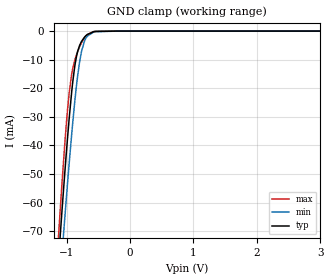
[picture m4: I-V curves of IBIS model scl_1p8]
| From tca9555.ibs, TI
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|   scl_1p8 Model
[Model]   scl_1p8
Model_type   Input
Vinl = 0.54
Vinh = 1.26
|   typ   min   max
|   (nom PVT)   (fast PVT)   (slow PVT)
C_comp   1.340e-12   1.280e-12   1.437e-12
[Model spec]
|subparameter
Vinl   0.54   0.495   0.585
Vinh   1.26   1.155   1.365
| Where nom  PVT is Nominal Process, 1.8V, 27C
|   Fast PVT is Strong Process,  1.95V, -40C
|   Slow PVT is Weak Process,   1.65V, 100C
[Voltage Range]   1.8   1.65   1.95
|Junction Temperature
[Temperature Range]   27   100   -40
[Power Clamp Reference]   1.8   1.65   1.95
[GND Clamp Reference]   0   0   0
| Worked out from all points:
|   GND clamp passes 1 mA (typ) near -0.65 V on its own axis
[GND Clamp]
|   Voltage   I(typ)   I(min)   I(max)
-1.8V     -319.1mA   -317.4mA   -335mA
-1.121V   -78.48mA   -93.12mA   -70.07mA
-1.071V   -62.62mA   -77.98mA   -53.03mA
-1.031V   -50.81mA   -66.56mA   -40.68mA
-961.2mV  -31.35mA   -47.09mA   -22.26mA
-918.6mV  -21.23mA   -36.09mA   -15.04mA
-871.8mV  -12.58mA   -25.07mA   -10.36mA
-824.4mV  -7.103mA   -15.61mA   -7.146mA
-763.8mV  -3.621mA   -7.099mA   -4.039mA
-675mV    -1.238mA   -1.806mA   -1.236mA
-180mV    0A         -74.39nA   0A
3.6V      0A         0A         0A
[POWER Clamp]
|   Voltage   I(typ)   I(min)   I(max)
-1.8V     0A         0A         0A
0V        0A         0A         0A
3.6V      0A         0A         0A
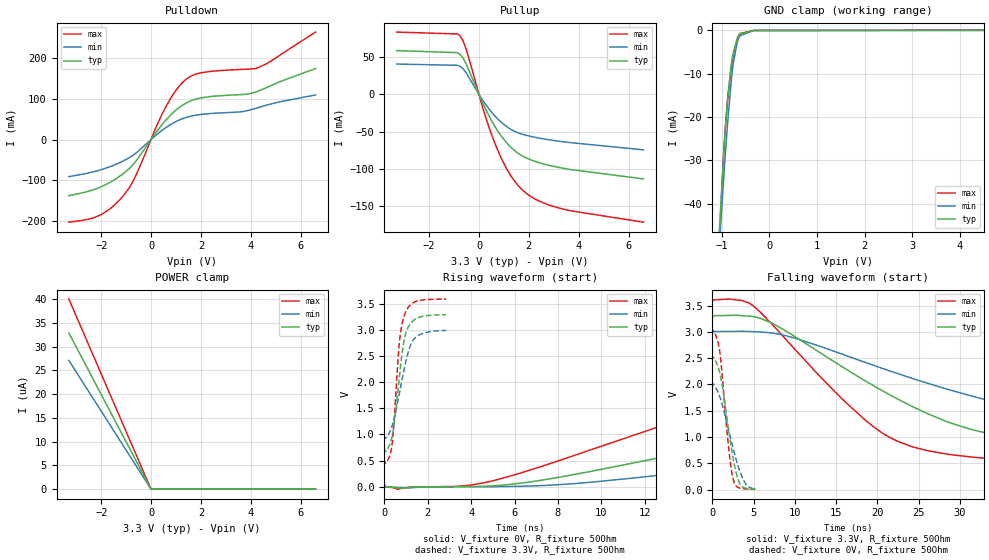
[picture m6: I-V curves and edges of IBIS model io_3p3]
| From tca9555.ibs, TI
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|   io_3p3 Model
[Model]   io_3p3
Model_type   I/O
Polarity   Non-Inverting
Enable   Active-Low
Vinl = 0.99
Vinh = 2.31
Vmeas = 1.65
Vref = 0
Cref = 100pF
Rref = 50
|   typ   min   max
|   (nom PVT)   (fast PVT)   (slow PVT)
C_comp   2.162e-12   2.013e-12   2.439e-12
[Model spec]
|subparameter
Vinl   0.99   0.90   1.08
Vinh   2.31   2.10   2.52
| Where nom  PVT is Nominal Process, 3.3V, 27C
|   Fast PVT is Strong Process,  3.6V, -40C
|   Slow PVT is Weak Process,   3V, 100C
[Voltage Range]   3.3   3   3.6
|Junction Temperature
[Temperature Range]   27   100   -40
[Pullup Reference]   3.3   3   3.6
[Pulldown Reference]   0   0   0
[Power Clamp Reference]   3.3   3   3.6
[GND Clamp Reference]   0   0   0
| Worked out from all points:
|   slope of the pulldown table from 0 to 0.495 V, typ, clamps not added: 12.2 ohm
|   slope of the pullup table from 0 to 0.495 V, typ, clamps not added: 14.3 ohm
|   GND clamp passes 1 mA (typ) near -0.63 V on its own axis
|   falling waveform, V_fixture 3.3V, R_fixture 50Ohm: 20-80 % time 18.9ns typ, 29.5ns min, 12.3ns max; typ from 3.3 V to 0.67 V
|   rising waveform, V_fixture 0V, R_fixture 50Ohm: 20-80 % time 23.3ns typ, 34.4ns min, 15.6ns max; typ from 0 V to 2.52 V
|   rising waveform, V_fixture 3.3V, R_fixture 50Ohm: 20-80 % time 445ps typ, 631ps min, 336ps max; typ from 0.67 V to 3.29 V
|   falling waveform, V_fixture 0V, R_fixture 50Ohm: 20-80 % time 1.46ns typ, 1.99ns min, 1.05ns max; typ from 2.52 V to 0.01 V
[Pulldown]
|   Voltage   I(typ)   I(min)   I(max)
-3.3V     -137.7mA   -91.07mA   -202.7mA
-2.379V   -124.6mA   -80.2mA    -193.3mA
-1.97V    -115mA     -73.34mA   -183mA
-1.1V     -82.89mA   -52.11mA   -136.9mA
-643.5mV  -55.72mA   -35.04mA   -92.27mA
564.3mV   45.71mA    28.08mA    77.22mA
1.056V    75.08mA    45.79mA    125.5mA
1.449V    90.95mA    55mA       149.8mA
2.055V    102.7mA    61.89mA    164.2mA
3.623V    110.2mA    67.99mA    172mA
4.228V    117.2mA    76.95mA    174.7mA
6.6V      174.1mA    109.3mA    263.5mA
[GND Clamp]
|   Voltage   I(typ)   I(min)   I(max)
-3.3V     -644.7mA   -564.3mA   -847.9mA
-1.056V   -46.75mA   -50.11mA   -48.67mA
-963.6mV  -29.21mA   -34.36mA   -28.58mA
-933mV    -23.97mA   -29.47mA   -23.2mA
-891.6mV  -17.58mA   -23.18mA   -17.36mA
-877.8mV  -15.68mA   -21.19mA   -15.74mA
-811.8mV  -8.601mA   -12.66mA   -9.426mA
-762.3mV  -5.282mA   -7.697mA   -5.882mA
-679.2mV  -1.991mA   -2.783mA   -2.007mA
-621mV    -845.1uA   -1.252mA   -735uA
-330mV    -37.34uA   -31.68uA   -47.87uA
6.6V      0A         0A         0A
[Pullup]
|   Voltage   I(typ)   I(min)   I(max)
-3.3V     58.79mA    40.72mA    83.64mA
-888mV    56.02mA    39.03mA    81.14mA
-762.3mV  53.62mA    37.69mA    78.53mA
-517.2mV  41.07mA    28.83mA    60.85mA
264mV     -19.87mA   -13.48mA   -30.34mA
717.6mV   -47.41mA   -31.89mA   -72.41mA
1.124V    -65.74mA   -43.68mA   -100.8mA
1.333V    -72.91mA   -48.04mA   -112.2mA
1.938V    -86.06mA   -55.4mA    -134.1mA
2.727V    -94.68mA   -60.6mA    -147.7mA
3.623V    -100.8mA   -64.68mA   -156.1mA
6.6V      -113.6mA   -74.54mA   -171.7mA
[POWER Clamp]
|   Voltage   I(typ)   I(min)   I(max)
-3.3V     32.91uA    27.11uA    40.04uA
-6mV      27.76nA    27.33nA    29.95nA
-2.4mV    585.7pA    2.087nA    0A
6.6V      0A         0A         0A
[Ramp]
R_load = 50
|   typ   min   max
dV/dt_r   1.51181/2.33896e-08   1.20398/3.48952e-08   1.81256/1.54921e-08
dV/dt_f   1.57799/1.88704e-08   1.24526/2.9355e-08   1.88984/1.22994e-08
[Falling Waveform]
V_fixture = 3.3V
V_fixture_min = 3V
V_fixture_max = 3.6V
R_fixture = 50Ohm
|   Time   V(typ)   V(min)   V(max)
0s        3.3V       3V         3.6V
4.906ns   3.291V     3.006V     3.501V
7.932ns   3.107V     2.961V     3.027V
15.42ns   2.368V     2.594V     1.773V
20.89ns   1.857V     2.291V     1.048V
25.99ns   1.452V     2.028V     742.5mV
31.83ns   1.127V     1.763V     612.5mV
47.52ns   822.6mV    1.286V     503.4mV
68.21ns   723.2mV    1.064V     467.2mV
200ns     670mV      924.6mV    450.3mV
[Rising Waveform]
V_fixture = 0V
V_fixture_min = 0V
V_fixture_max = 0V
R_fixture = 50Ohm
|   Time   V(typ)   V(min)   V(max)
0s        297.5uV    324.3uV    250.2uV
4.906ns   13.56mV    461.1uV    103mV
8.87ns    242.3mV    62.31mV    613.1mV
16.17ns   843.6mV    385.6mV    1.604V
22.53ns   1.326V     685.9mV    2.28V
25.99ns   1.552V     839.2mV    2.524V
31.83ns   1.866V     1.072V     2.738V
45.13ns   2.251V     1.474V     2.907V
67.57ns   2.429V     1.807V     2.986V
144ns     2.516V     1.994V     3.02V
[Rising Waveform]
V_fixture = 3.3V
V_fixture_min = 3V
V_fixture_max = 3.6V
R_fixture = 50Ohm
|   Time   V(typ)   V(min)   V(max)
0s        669.8mV    922.9mV    450.2mV
233.8ps   794.9mV    1.036V     577mV
371.4ps   997.1mV    1.184V     873.6mV
485.9ps   1.318V     1.368V     1.517V
673ps     2.041V     1.751V     2.688V
772.1ps   2.407V     1.962V     3.022V
952.3ps   2.885V     2.327V     3.312V
1.171ns   3.098V     2.671V     3.466V
1.433ns   3.205V     2.853V     3.54V
2.846ns   3.287V     2.987V     3.586V
[Falling Waveform]
V_fixture = 0V
V_fixture_min = 0V
V_fixture_max = 0V
R_fixture = 50Ohm
|   Time   V(typ)   V(min)   V(max)
0s        2.521V     2.01V      3.021V
499.9ps   2.41V      1.913V     2.898V
896.6ps   2.223V     1.767V     2.626V
1.146ns   2.029V     1.644V     2.261V
1.918ns   1.192V     1.165V     875mV
2.478ns   632mV      808.7mV    227mV
2.848ns   346.5mV    592.1mV    72.32mV
3.332ns   110.3mV    351.4mV    27.84mV
4.112ns   24.55mV    93.58mV    12.44mV
5.224ns   9.864mV    16.1mV     7.948mV
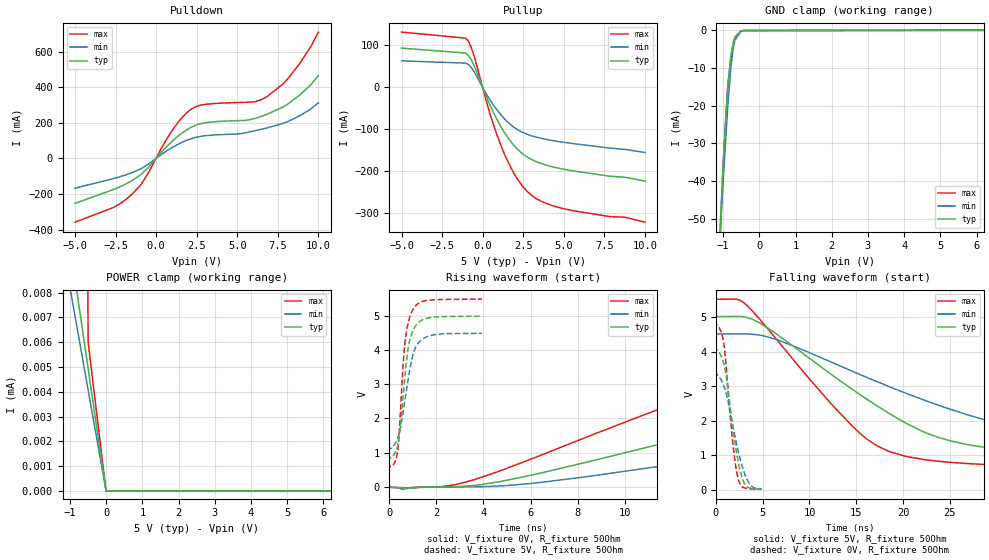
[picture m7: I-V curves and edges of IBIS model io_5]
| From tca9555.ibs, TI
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|   io_5 Model
[Model]   io_5
Model_type   I/O
Polarity   Non-Inverting
Enable   Active-Low
Vinl = 1.5
Vinh = 3.5
Vmeas = 2.5
Vref = 0
Cref = 100pF
Rref = 50
|   typ   min   max
|   (nom PVT)   (fast PVT)   (slow PVT)
C_comp   2.226e-12   2.041e-12   2.515e-12
[Model spec]
|subparameter
Vinl   1.5   1.35   1.65
Vinh   3.5   3.15   3.85
| Where nom  PVT is Nominal Process, 5V, 27C
|   Fast PVT is Strong Process,  5.5V, -40C
|   Slow PVT is Weak Process,   4.5V, 100C
[Voltage Range]   5   4.5   5.5
|Junction Temperature
[Temperature Range]   27   100   -40
[Pullup Reference]   5   4.5   5.5
[Pulldown Reference]   0   0   0
[Power Clamp Reference]   5   4.5   5.5
[GND Clamp Reference]   0   0   0
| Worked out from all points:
|   slope of the pulldown table from 0 to 0.75 V, typ, clamps not added: 10 ohm
|   slope of the pullup table from 0 to 0.75 V, typ, clamps not added: 11.2 ohm
|   GND clamp passes 1 mA (typ) near -0.59 V on its own axis
|   POWER clamp passes 1 mA (typ) near -3.66 V on its own axis
|   falling waveform, V_fixture 5V, R_fixture 50Ohm: 20-80 % time 14ns typ, 20.9ns min, 9.66ns max; typ from 5 V to 0.844 V
|   rising waveform, V_fixture 0V, R_fixture 50Ohm: 20-80 % time 17.7ns typ, 25.8ns min, 12.2ns max; typ from 0 V to 4.06 V
|   rising waveform, V_fixture 5V, R_fixture 50Ohm: 20-80 % time 371ps typ, 495ps min, 302ps max; typ from 0.843 V to 4.99 V
|   falling waveform, V_fixture 0V, R_fixture 50Ohm: 20-80 % time 1.25ns typ, 1.6ns min, 956ps max; typ from 4.06 V to 0.014 V
[Pulldown]
|   Voltage   I(typ)   I(min)   I(max)
-5V       -252.6mA   -166.9mA   -358mA
-2.63V    -174.6mA   -113.1mA   -275.5mA
-1.486V   -124.2mA   -79.71mA   -201.1mA
-913.5mV  -88.96mA   -56.77mA   -145mA
950mV     92.89mA    59.13mA    151.3mA
2.21V     176.9mA    112mA      279.2mA
3.102V    201.4mA    128.1mA    304.4mA
6.093V    224.2mA    155.5mA    318mA
6.84V     248.2mA    171.5mA    347.4mA
8.117V    305mA      206.9mA    447.2mA
9.537V    413.7mA    278.2mA    628.1mA
10V       464.6mA    312.1mA    709.2mA
[GND Clamp]
|   Voltage   I(typ)   I(min)   I(max)
-5V       -1.377A    -1.093A    -1.874A
-1.125V   -60.62mA   -62.32mA   -65.22mA
-1.05V    -45.21mA   -48.79mA   -46.81mA
-996mV    -34.8mA    -39.48mA   -34.71mA
-880.5mV  -15.83mA   -21.37mA   -15.84mA
-869.5mV  -14.4mA    -19.82mA   -14.64mA
-788mV    -6.735mA   -9.941mA   -7.489mA
-720mV    -3.274mA   -4.608mA   -3.518mA
-675.5mV  -1.866mA   -2.608mA   -1.86mA
-500mV    -129.4uA   -187.3uA   -112.2uA
10V       0A         0A         0A
[Pullup]
|   Voltage   I(typ)   I(min)   I(max)
-5V       93.53mA    63.13mA    131.8mA
-1.051V   81.85mA    57.71mA    117.5mA
-895mV    76.75mA    54.76mA    110.7mA
-500mV    49.2mA     35.34mA    71.52mA
560.5mV   -51.95mA   -36.49mA   -76.76mA
1.3V      -105.5mA   -73.5mA    -155.8mA
2.111V    -146.6mA   -100.5mA   -217.3mA
3.019V    -172.6mA   -115.9mA   -258.2mA
3.699V    -183.3mA   -122.8mA   -274mA
4.896V    -195.1mA   -131mA     -289.2mA
8.772V    -214.9mA   -148.4mA   -310.2mA
10V       -224.1mA   -155.7mA   -322.2mA
[POWER Clamp]
|   Voltage   I(typ)   I(min)   I(max)
-5V       480.2mA    80.28mA    1.105A
-3.114V   31.03uA    25.57uA    841.6uA
-500mV    4.942uA    4.078uA    6.008uA
-6mV      11.2nA     15.99nA    0A
10V       0A         0A         0A
[Ramp]
R_load = 50
|   typ   min   max
dV/dt_r   2.43332/1.76975e-08   2.0021/2.57603e-08   2.8654/1.21809e-08
dV/dt_f   2.49351/1.39845e-08   2.02713/2.09078e-08   2.94596/9.66266e-09
[Falling Waveform]
V_fixture = 5V
V_fixture_min = 4.5V
V_fixture_max = 5.5V
R_fixture = 50Ohm
|   Time   V(typ)   V(min)   V(max)
0s        5V         4.5V       5.5V
2.133ns   5.021V     4.516V     5.524V
3.289ns   4.992V     4.516V     5.347V
6.669ns   4.473V     4.33V      4.294V
16.21ns   2.605V     3.243V     1.448V
18.52ns   2.208V     2.986V     1.103V
22.41ns   1.649V     2.579V     862.6mV
33.25ns   1.101V     1.74V      681.9mV
49.3ns    933.1mV    1.339V     621mV
150ns     844.1mV    1.121V     590.1mV
[Rising Waveform]
V_fixture = 0V
V_fixture_min = 0V
V_fixture_max = 0V
R_fixture = 50Ohm
|   Time   V(typ)   V(min)   V(max)
0s        388.6uV    415uV      335.8uV
2.213ns   -1.931mV   -2.458mV   8.125mV
3.587ns   41.48mV    2.836mV    208.1mV
13.19ns   1.529V     776.4mV    2.701V
18.52ns   2.337V     1.302V     3.792V
22.41ns   2.832V     1.656V     4.227V
27.25ns   3.294V     2.043V     4.452V
41.06ns   3.795V     2.79V      4.659V
58.3ns    3.952V     3.117V     4.732V
150ns     4.056V     3.337V     4.776V
[Rising Waveform]
V_fixture = 5V
V_fixture_min = 4.5V
V_fixture_max = 5.5V
R_fixture = 50Ohm
|   Time   V(typ)   V(min)   V(max)
0s        843.1mV    1.117V     589.9mV
261.1ps   1.021V     1.284V     761.3mV
371.4ps   1.271V     1.459V     1.153V
463.5ps   1.718V     1.701V     2.103V
661.7ps   3.225V     2.532V     4.207V
828.2ps   4.167V     3.267V     4.871V
989.6ps   4.544V     3.827V     5.17V
1.203ns   4.777V     4.18V      5.344V
1.712ns   4.944V     4.414V     5.457V
3.929ns   4.987V     4.488V     5.487V
[Falling Waveform]
V_fixture = 0V
V_fixture_min = 0V
V_fixture_max = 0V
R_fixture = 50Ohm
|   Time   V(typ)   V(min)   V(max)
0s        4.059V     3.346V     4.777V
524ps     3.892V     3.195V     4.595V
855.6ps   3.641V     3.004V     4.216V
1.088ns   3.313V     2.8V       3.584V
1.731ns   1.949V     1.958V     1.529V
2.068ns   1.296V     1.5V       765.2mV
2.334ns   870.3mV    1.168V     361.3mV
3.106ns   144.4mV    431.8mV    42.58mV
3.86ns    30.23mV    84.37mV    17.6mV
4.878ns   13.65mV    18.5mV     12.03mV
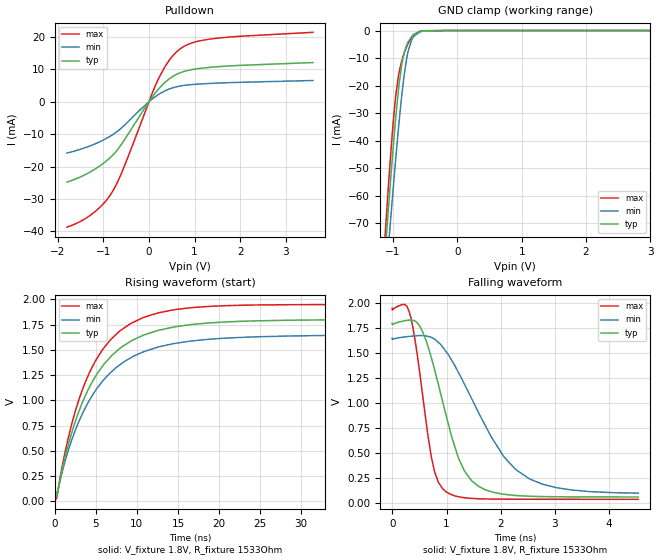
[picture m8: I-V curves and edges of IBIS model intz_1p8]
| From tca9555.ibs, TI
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|   intz_1p8 Model
[Model]   intz_1p8
Model_type   Open_sink
Polarity   Non-Inverting
Vmeas = 0.9
Vref = 1.8
Cref = 100pF
Rref = 1533
|   typ   min   max
|   (nom PVT)   (fast PVT)   (slow PVT)
C_comp   1.340e-12   1.310e-12   1.437e-12
| Where nom  PVT is Nominal Process, 1.8V, 27C
|   Fast PVT is Strong Process,  1.95V, -40C
|   Slow PVT is Weak Process,   1.65V, 100C
[Voltage Range]   1.8   1.65   1.95
|Junction Temperature
[Temperature Range]   27   100   -40
[Pullup Reference]   1.8   1.65   1.95
[Pulldown Reference]   0   0   0
[Power Clamp Reference]   1.8   1.65   1.95
[GND Clamp Reference]   0   0   0
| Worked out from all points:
|   slope of the pulldown table from 0 to 0.27 V, typ, clamps not added: 56.2 ohm
|   GND clamp passes 1 mA (typ) near -0.64 V on its own axis
|   falling waveform, V_fixture 1.8V, R_fixture 1533Ohm: 20-80 % time 535ps typ, 963ps min, 299ps max; typ from 1.8 V to 0.058 V
|   rising waveform, V_fixture 1.8V, R_fixture 1533Ohm: 20-80 % time 5.85ns typ, 6.39ns min, 5.36ns max; typ from 0.056 V to 1.8 V
[Pulldown]
|   Voltage   I(typ)   I(min)   I(max)
-1.8V     -24.79mA   -15.82mA   -38.7mA
-1.287V   -21.65mA   -13.59mA   -35.01mA
-1.055V   -19.54mA   -12.18mA   -32.24mA
-813.3mV  -16.73mA   -10.29mA   -27.97mA
-552mV    -12.01mA   -7.422mA   -20.22mA
36mV      778.2uA    447.2uA    1.414mA
201.4mV   3.793mA    2.164mA    6.871mA
430.8mV   6.899mA    3.856mA    12.53mA
682.2mV   8.919mA    4.846mA    16.3mA
1.003V    10.06mA    5.366mA    18.42mA
1.421V    10.72mA    5.702mA    19.48mA
3.6V      12.09mA    6.544mA    21.42mA
[GND Clamp]
|   Voltage   I(typ)   I(min)   I(max)
-1.8V     -328.2mA   -322.4mA   -349.4mA
-1.153V   -91.61mA   -104.2mA   -85.93mA
-1.071V   -65.1mA    -79.27mA   -56.97mA
-1.033V   -53.56mA   -68.24mA   -44.71mA
-961.2mV  -33.1mA    -48.02mA   -24.88mA
-916.6mV  -22.28mA   -36.4mA    -16.87mA
-865.9mV  -12.89mA   -24.46mA   -11.41mA
-822.6mV  -7.86mA    -15.86mA   -8.12mA
-763.8mV  -4.189mA   -7.541mA   -4.669mA
-673.2mV  -1.403mA   -2.006mA   -1.395mA
-180mV    0A         -87.16nA   0A
3.6V      0A         0A         0A
[POWER Clamp]
|   Voltage   I(typ)   I(min)   I(max)
-1.8V     0A         0A         0A
0V        0A         0A         0A
3.6V      0A         0A         0A
[Ramp]
R_load = 1533
|   typ   min   max
dV/dt_r   1.04651/5.85609e-09  0.936889/6.41863e-09   1.14991/5.36597e-09
dV/dt_f   1.0465/5.36101e-10   0.936882/9.71383e-10   1.14993/2.99485e-10
[Falling Waveform]
V_fixture = 1.8V
V_fixture_min = 1.65V
V_fixture_max = 1.95V
R_fixture = 1533Ohm
|   Time   V(typ)   V(min)   V(max)
0s        1.8V       1.65V      1.95V
313.7ps   1.831V     1.668V     1.913V
497.4ps   1.779V     1.676V     1.337V
718.2ps   1.458V     1.659V     464.1mV
991.8ps   877.7mV    1.515V     109.7mV
1.214ns   456.9mV    1.312V     61.28mV
1.463ns   219.6mV    1.044V     43.55mV
2.273ns   72.4mV     334.4mV    35.28mV
3.017ns   60.18mV    152mV      34.73mV
4.534ns   57.8mV     96.1mV     34.24mV
[Rising Waveform]
V_fixture = 1.8V
V_fixture_min = 1.65V
V_fixture_max = 1.95V
R_fixture = 1533Ohm
|   Time   V(typ)   V(min)   V(max)
0s        55.83mV    88.53mV    33.46mV
233ps     54.68mV    85.83mV    34.15mV
991.8ps   345.1mV    316.1mV    381.5mV
1.989ns   657.6mV    588.6mV    741.2mV
3.724ns   1.047V     926.9mV    1.182V
5.799ns   1.337V     1.189V     1.501V
9.248ns   1.586V     1.422V     1.762V
12.58ns   1.694V     1.529V     1.867V
18.58ns   1.766V     1.604V     1.93V
44.58ns   1.8V       1.648V     1.95V
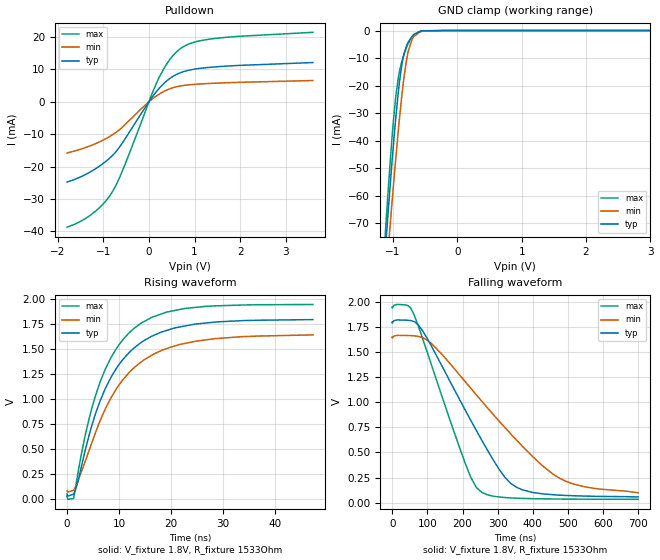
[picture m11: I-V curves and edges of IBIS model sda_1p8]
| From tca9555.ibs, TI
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|   sda_1p8 Model
[Model]   sda_1p8
Model_type   I/O_open_drain
Polarity   Non-Inverting
Vinl = 0.54
Vinh = 1.26
Vmeas = 0.9
Vref = 1.8
Cref = 100pF
Rref = 1533
|   typ   min   max
|   (nom PVT)   (fast PVT)   (slow PVT)
C_comp   1.437e-12   1.371e-12   1.546e-12
[Model spec]
|subparameter
Vinl   0.54   0.495   0.585
Vinh   1.26   1.155   1.365
| Where nom  PVT is Nominal Process, 1.8V, 27C
|   Fast PVT is Strong Process,  1.95V, -40C
|   Slow PVT is Weak Process,   1.65V, 100C
[Voltage Range]   1.8   1.65   1.95
|Junction Temperature
[Temperature Range]   27   100   -40
[Pullup Reference]   1.8   1.65   1.95
[Pulldown Reference]   0   0   0
[Power Clamp Reference]   1.8   1.65   1.95
[GND Clamp Reference]   0   0   0
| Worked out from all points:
|   slope of the pulldown table from 0 to 0.27 V, typ, clamps not added: 56.2 ohm
|   GND clamp passes 1 mA (typ) near -0.63 V on its own axis
|   falling waveform, V_fixture 1.8V, R_fixture 1533Ohm: 20-80 % time 163ns typ, 240ns min, 112ns max; typ from 1.8 V to 0.057 V
|   rising waveform, V_fixture 1.8V, R_fixture 1533Ohm: 20-80 % time 8.52ns typ, 9.65ns min, 7.65ns max; typ from 0.056 V to 1.8 V
[Pulldown]
|   Voltage   I(typ)   I(min)   I(max)
-1.8V     -24.79mA   -15.82mA   -38.7mA
-1.287V   -21.65mA   -13.59mA   -35.01mA
-1.055V   -19.54mA   -12.18mA   -32.24mA
-813.3mV  -16.73mA   -10.29mA   -27.97mA
-552mV    -12.01mA   -7.422mA   -20.22mA
36mV      778.2uA    447.2uA    1.414mA
201.4mV   3.793mA    2.164mA    6.871mA
430.8mV   6.899mA    3.855mA    12.53mA
682.2mV   8.919mA    4.846mA    16.3mA
1.003V    10.06mA    5.366mA    18.42mA
1.421V    10.72mA    5.702mA    19.48mA
3.6V      12.09mA    6.544mA    21.42mA
[GND Clamp]
|   Voltage   I(typ)   I(min)   I(max)
-1.8V     -325.3mA   -319.3mA   -347.4mA
-1.153V   -91.23mA   -103.7mA   -85.91mA
-1.071V   -65.01mA   -79.02mA   -57.17mA
-1.031V   -53.06mA   -67.59mA   -44.44mA
-959.4mV  -32.85mA   -47.62mA   -24.87mA
-914.7mV  -22.14mA   -36.11mA   -16.95mA
-864mV    -12.87mA   -24.32mA   -11.52mA
-820.8mV  -7.904mA   -15.85mA   -8.198mA
-762.1mV  -4.229mA   -7.607mA   -4.71mA
-672.9mV  -1.438mA   -2.076mA   -1.429mA
-180mV    0A         -90.2nA    0A
3.6V      0A         0A         0A
[POWER Clamp]
|   Voltage   I(typ)   I(min)   I(max)
-1.8V     0A         0A         0A
0V        0A         0A         0A
3.6V      0A         0A         0A
[Ramp]
R_load = 1533
|   typ   min   max
dV/dt_r   1.0465/8.52951e-09   0.936877/9.72469e-09   1.14992/7.65398e-09
dV/dt_f   1.04555/1.63106e-07   0.930424/2.39469e-07   1.14979/1.12222e-07
[Falling Waveform]
V_fixture = 1.8V
V_fixture_min = 1.65V
V_fixture_max = 1.95V
R_fixture = 1533Ohm
|   Time   V(typ)   V(min)   V(max)
0s        1.8V       1.65V      1.95V
43.85ns   1.816V     1.664V     1.964V
59.92ns   1.805V     1.662V     1.888V
109.2ns   1.574V     1.592V     1.396V
207.3ns   924.4mV    1.206V     395.8mV
255.3ns   619mV      1.008V     101.9mV
321ns     251.7mV    747.4mV    51.44mV
369ns     130.1mV    567.6mV    43.08mV
491.7ns   72.57mV    217.5mV    36.22mV
700ns     57.42mV    99.29mV    33.68mV
[Rising Waveform]
V_fixture = 1.8V
V_fixture_min = 1.65V
V_fixture_max = 1.95V
R_fixture = 1533Ohm
|   Time   V(typ)   V(min)   V(max)
0s        55.83mV    88.53mV    33.46mV
1.249ns   52.49mV    89.19mV    8.533mV
1.922ns   146.9mV    163mV      211.3mV
3.627ns   519.5mV    399.6mV    671.4mV
6.456ns   997.2mV    798.9mV    1.186V
9.515ns   1.312V     1.107V     1.51V
12.83ns   1.511V     1.313V     1.708V
17.49ns   1.659V     1.474V     1.843V
24.63ns   1.753V     1.581V     1.92V
47.32ns   1.799V     1.646V     1.95V
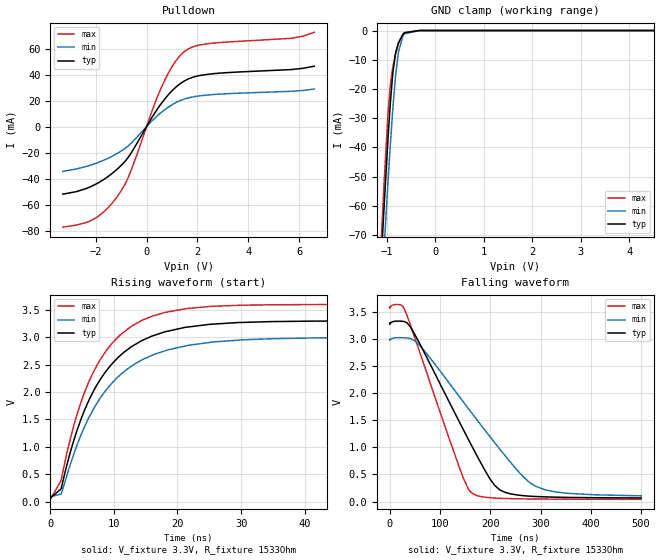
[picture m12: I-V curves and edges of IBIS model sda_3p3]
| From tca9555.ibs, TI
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|   sda_3p3 Model
[Model]   sda_3p3
Model_type   I/O_open_drain
Polarity   Non-Inverting
Vinl = 0.99
Vinh = 2.31
Vmeas = 1.65
Vref = 3.3
Cref = 100pF
Rref = 1533
|   typ   min   max
|   (nom PVT)   (fast PVT)   (slow PVT)
C_comp   1.404e-12   1.340e-12   1.546e-12
[Model spec]
|subparameter
Vinl   0.99   0.90   1.08
Vinh   2.31   2.10   2.52
| Where nom  PVT is Nominal Process, 3.3V, 27C
|   Fast PVT is Strong Process,  3.6V, -40C
|   Slow PVT is Weak Process,   3V, 100C
[Voltage Range]   3.3   3   3.6
|Junction Temperature
[Temperature Range]   27   100   -40
[Pullup Reference]   3.3   3   3.6
[Pulldown Reference]   0   0   0
[Power Clamp Reference]   3.3   3   3.6
[GND Clamp Reference]   0   0   0
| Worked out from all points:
|   slope of the pulldown table from 0 to 0.495 V, typ, clamps not added: 32.1 ohm
|   GND clamp passes 1 mA (typ) near -0.65 V on its own axis
|   falling waveform, V_fixture 3.3V, R_fixture 1533Ohm: 20-80 % time 107ns typ, 144ns min, 78.8ns max; typ from 3.3 V to 0.066 V
|   rising waveform, V_fixture 3.3V, R_fixture 1533Ohm: 20-80 % time 8.14ns typ, 8.95ns min, 7.34ns max; typ from 0.062 V to 3.3 V
[Pulldown]
|   Voltage   I(typ)   I(min)   I(max)
-3.3V     -51.89mA   -34.4mA    -77.26mA
-2.379V   -47.56mA   -30.65mA   -73.7mA
-1.97V    -43.9mA    -28.04mA   -69.8mA
-1.536V   -38.59mA   -24.48mA   -62.62mA
-1.1V     -31.65mA   -19.92mA   -52.2mA
-643.5mV  -21.27mA   -13.39mA   -35.18mA
564.3mV   17.44mA    10.72mA    29.44mA
1.056V    28.63mA    17.47mA    47.82mA
1.47V     34.92mA    21.11mA    57.44mA
2.436V    40.28mA    24.37mA    63.77mA
5.66V     43.8mA     27.11mA    67.8mA
6.6V      46.44mA    28.87mA    72.45mA
[GND Clamp]
|   Voltage   I(typ)   I(min)   I(max)
-3.3V     -926.2mA   -871.9mA   -1.044A
-1.112V   -77.6mA    -90.96mA   -70.83mA
-1.079V   -67.16mA   -81.1mA    -59.45mA
-1.063V   -62.05mA   -76.24mA   -53.93mA
-976.8mV  -37.06mA   -51.94mA   -28.55mA
-927.6mV  -24.68mA   -39mA      -18.6mA
-873mV    -14.01mA   -25.99mA   -12.17mA
-819mV    -7.623mA   -15.3mA    -7.963mA
-762mV    -4.156mA   -7.451mA   -4.62mA
-633mV    -770.7uA   -1.132mA   -679.3uA
-330mV    -886.7nA   -3.354uA   -140.4nA
6.6V      0A         0A         0A
[POWER Clamp]
|   Voltage   I(typ)   I(min)   I(max)
-3.3V     0A         0A         0A
0V        0A         0A         0A
6.6V      0A         0A         0A
[Ramp]
R_load = 1533
|   typ   min   max
dV/dt_r   1.94296/8.14112e-09   1.74584/8.95817e-09   2.13619/7.3484e-09
dV/dt_f   1.9406/1.07e-07   1.7366/1.44345e-07   2.13567/7.87102e-08
[Falling Waveform]
V_fixture = 3.3V
V_fixture_min = 3V
V_fixture_max = 3.6V
R_fixture = 1533Ohm
|   Time   V(typ)   V(min)   V(max)
0s        3.3V       3V         3.6V
29.75ns   3.325V     3.027V     3.546V
58.01ns   2.947V     2.901V     2.807V
139.5ns   1.452V     1.926V     603.7mV
163.6ns   1.02V      1.63V      156mV
199ns     423.1mV    1.203V     70.99mV
219ns     215.1mV    967.3mV    59.84mV
288.8ns   93.44mV    289.1mV    46.72mV
348.8ns   76.83mV    156.9mV    43.26mV
500ns     65.66mV    105.7mV    40.55mV
[Rising Waveform]
V_fixture = 3.3V
V_fixture_min = 3V
V_fixture_max = 3.6V
R_fixture = 1533Ohm
|   Time   V(typ)   V(min)   V(max)
0s        61.71mV    90.25mV    39.67mV
1.699ns   230.6mV    133.6mV    382.1mV
3.074ns   867.4mV    649.9mV    1.111V
4.281ns   1.325V     1.055V     1.62V
6.863ns   2.034V     1.704V     2.383V
9.878ns   2.538V     2.186V     2.912V
14.47ns   2.944V     2.59V      3.313V
18.58ns   3.115V     2.774V     3.467V
25.72ns   3.242V     2.916V     3.567V
58.01ns   3.3V       2.999V     3.6V
